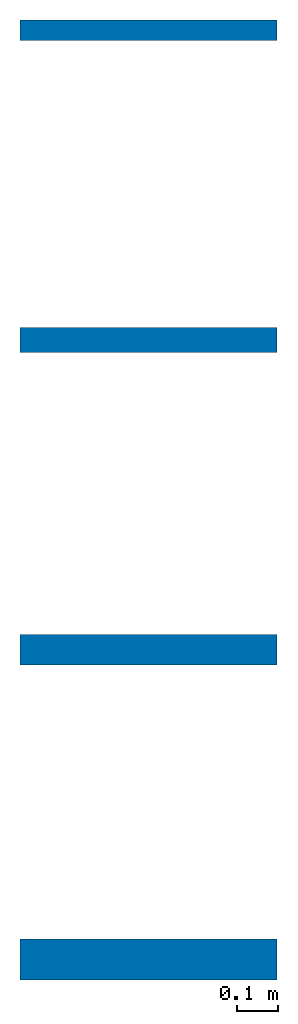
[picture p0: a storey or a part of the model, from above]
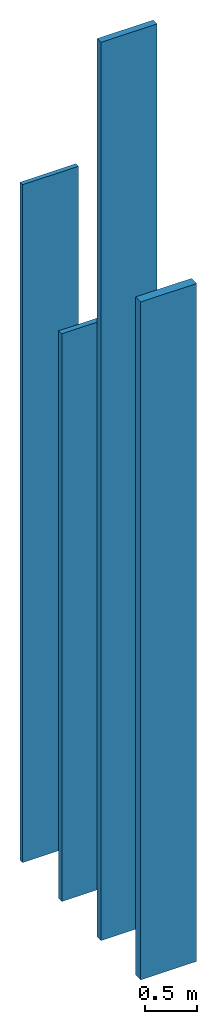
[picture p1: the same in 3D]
Properties of the parts of a building model (IFC2X3)

# File
Description: ViewDefinition [CoordinationView_V2.0]
File name: 0001
Time: 2018-02-28T12:43:13
Written by: The EXPRESS Data Manager Version 5.02.0100.07 : 28 Aug 2013
Made in: 20140606_1530(x64) - Exporter 15.6.0.0 - Alternate UI 15.6.0.0
Comment: STEP Physical File produced by: The EXPRESS Data Manager Version 5.02.0100.07 : 28 Aug 2013 * Module: EDMstepFileFactory/EDMstandAlone * Creation date: Wed Feb 28 12:43:13 2018 * Host: BRUTUS-02 * Database: C:\Users\MIGUEL~1\AppData\Local\Temp\{2AA0D388-3C4A-43AB-BBA2-5D648CE83F9A}\ifc * Database version: 5507 * Database creation date: Wed Feb 28 12:43:13 2018 * Schema: IFC2X3 * Model: DataRepository.ifc * Model creation date: Wed Feb 28 12:43:13 2018 * Header model: DataRepository.ifc_HeaderModel * Header model creation date: Wed Feb 28 12:43:13 2018 * EDMuser: sdai-user * EDMgroup: sdai-group * License ID and type: 5605 : Permanent license. Expiry date: * EDMstepFileFactory options: 020000

# IfcProject, 0001
LongName: Project Name; Phase: Project Status

# IfcSite, Default
RefLatitude: 42, 21, 30, 344238; RefLongitude: -71, -3, -35, -194702; RefElevation: 0 mm
Other - Category: Project Information; Client Name: Owner; Project Address: ## Street City, State Zip; Project Issue Date: Issue Date; Project Name: Project Name; Project Number: 0001; Project Status: Project Status

# IfcBuilding
Pset_BuildingCommon - NumberOfStoreys: 1
Other - Category: Project Information; Client Name: Owner; Project Address: ## Street City, State Zip; Project Issue Date: Issue Date; Project Name: Project Name; Project Number: 0001; Project Status: Project Status

# IfcBuildingStorey, Референтни ниво
LongName: Референтни ниво; Elevation: 0 mm
Other - Category: Levels; Family Name: Level; Family: Level: 8mm Head; Family and Type: Level: 8mm Head; Type: Level: 8mm Head; Type Id: Level: 8mm Head
Constraints - Elevation: 0 mm; Elevation Base: Project Base Point
Dimensions - Computation Height: 0 mm
Identity Data - Structural: no; Building Story: yes; Name: Референтни ниво; Type Name: 8mm Head
Graphics - Color: 0; Line Pattern: Center; Line Weight: 1; Symbol at End 1 Default: no; Symbol at End 2 Default: yes

# IfcWallStandardCase: Basic Wall:Knauf Insulation - Decibel - 100 mm - 100 x 8000 x 625 mm, Basic Wall:Knauf Insulation - Decibel - 100 mm - 100 x 8000 x 625 mm:207778
In: Референтни ниво
Type - PredefinedType: STANDARD; Material: Knauf Insulation - Decibel - 100 mm - 100 x 8000 x 625 mm 100 mm
Type - Analytical Properties - Roughness: 3; Absorptance: 0.7; Heat Transfer Coefficient (U): 0.38; Thermal mass: 958.5; Thermal Resistance (R): 2.63158
Type - Construction - Function: Exterior; Wrapping at Inserts: Do not wrap; Width: 100 mm
Type - Graphics - Coarse Scale Fill Color: 3951475
Type - Identity Data - Description: proizvod od staklene mineralne vune sa ECOSE® Technology. Pruža visoku zaštitu u pogledu termičke, zvučne i zaštite od požara. Proizvodi se sa širinom od 625mm.; KontaktE-mail: edin.dalifi@knaufinsulation.com; KontaktTelefon: +3811113310800; Manufacturer: Knauf Insulation; Model: Decibel; No.: 85; Type Comments: namenjen je za primenu u unutrašnjim zidovima kao ispuna koja apsorbuje zvuk u pregradnim zidovima sa visokim akustičkim zahtevima kada su u pitanju suvomontažne konstrukcije sa gips-kartonskim pločama. Ukoliko se materijal upotrebljava u konstrukcijama sa različitim režimima grejanja, treba postaviti parnu branu sa toplije strane izolacionog materijala, ka strani koja je okrenuta grejanom prostoru, da bi se sprečilo prodiranje unutrašnje vlage u materijal.; Type Name: Knauf Insulation - Decibel - 100 mm - 100 x 8000 x 625 mm; URL: http://www.knaufinsulation.rs/sr/staklena-vuna/decibel
Type - Materials and Finishes - Structural Material: Knauf Insulation - Decibel - 100 mm - 100 x 8000 x 625 mm
Type - Other - Category: Walls; Family Name: Basic Wall
Constraints - Base Constraint: Level: Референтни ниво; Base Extension Distance: 0 mm; Base is Attached: no; Base Offset: 0 mm; Location Line: Wall Centerline; Related to Mass: no; Room Bounding: yes; Top Extension Distance: 0 mm; Top is Attached: no; Top Offset: 0 mm; Unconnected Height: 8000 mm
Dimensions - Area: 5 m2; Length: 625 mm; Volume: 0.5 m3
Other - Family: Basic Wall: Knauf Insulation - Decibel - 100 mm - 100 x 8000 x 625 mm; Family and Type: Basic Wall: Knauf Insulation - Decibel - 100 mm - 100 x 8000 x 625 mm; Type: Basic Wall: Knauf Insulation - Decibel - 100 mm - 100 x 8000 x 625 mm; Type Id: Basic Wall: Knauf Insulation - Decibel - 100 mm - 100 x 8000 x 625 mm
Phasing - Phase Created: New Construction
Structural - Enable Analytical Model: no; Structural: no; Structural Usage: Non-bearing
Pset_WallCommon - LoadBearing: no; ExtendToStructure: no; IsExternal: yes; Reference: Knauf Insulation - Decibel - 100 mm - 100 x 8000 x 625 mm; ThermalTransmittance: 0.38 kg/K/s3
Pset_ManufacturerTypeInformation - Manufacturer: Knauf Insulation
Knauf Insulation Materijali - Zidovi - No.: 85

# IfcWallStandardCase: Basic Wall:Knauf Insulation - Decibel - 50 mm -50 x 8000 x 625 mm, Basic Wall:Knauf Insulation - Decibel - 50 mm -50 x 8000 x 625 mm:207353
In: Референтни ниво
Type - PredefinedType: STANDARD; Material: Knauf Insulation - Decibel - 50 mm - 50 x 8000 x 625 mm 50 mm
Type - Analytical Properties - Absorptance: 0.7; Heat Transfer Coefficient (U): 0.76; Roughness: 3; Thermal mass: 479.25; Thermal Resistance (R): 1.31579
Type - Construction - Function: Exterior; Width: 50 mm; Wrapping at Inserts: Do not wrap
Type - Graphics - Coarse Scale Fill Color: 3951475
Type - Identity Data - Description: proizvod od staklene mineralne vune sa ECOSE® Technology. Pruža visoku zaštitu u pogledu termičke, zvučne i zaštite od požara. Proizvodi se sa širinom od 625mm.; KontaktE-mail: edin.dalifi@knaufinsulation.com; KontaktTelefon: +3811113310800; Manufacturer: Knauf Insulation; Model: Decibel; No.: 82; Type Comments: namenjen je za primenu u unutrašnjim zidovima kao ispuna koja apsorbuje zvuk u pregradnim zidovima sa visokim akustičkim zahtevima kada su u pitanju suvomontažne konstrukcije sa gips-kartonskim pločama. Ukoliko se materijal upotrebljava u konstrukcijama sa različitim režimima grejanja, treba postaviti parnu branu sa toplije strane izolacionog materijala, ka strani koja je okrenuta grejanom prostoru, da bi se sprečilo prodiranje unutrašnje vlage u materijal.; Type Name: Knauf Insulation - Decibel - 50 mm -50 x 8000 x 625 mm; URL: http://www.knaufinsulation.rs/sr/staklena-vuna/decibel
Type - Materials and Finishes - Structural Material: Knauf Insulation - Decibel - 50 mm - 50 x 8000 x 625 mm
Type - Other - Category: Walls; Family Name: Basic Wall
Constraints - Base Constraint: Level: Референтни ниво; Base Extension Distance: 0 mm; Base is Attached: no; Base Offset: 0 mm; Location Line: Wall Centerline; Related to Mass: no; Room Bounding: yes; Top Extension Distance: 0 mm; Top is Attached: no; Top Offset: 0 mm; Unconnected Height: 8000 mm
Dimensions - Area: 5 m2; Length: 625 mm; Volume: 0.25 m3
Other - Family: Basic Wall: Knauf Insulation - Decibel - 50 mm -50 x 8000 x 625 mm; Family and Type: Basic Wall: Knauf Insulation - Decibel - 50 mm -50 x 8000 x 625 mm; Type: Basic Wall: Knauf Insulation - Decibel - 50 mm -50 x 8000 x 625 mm; Type Id: Basic Wall: Knauf Insulation - Decibel - 50 mm -50 x 8000 x 625 mm
Phasing - Phase Created: New Construction
Structural - Enable Analytical Model: no; Structural: no; Structural Usage: Non-bearing
Pset_WallCommon - Reference: Knauf Insulation - Decibel - 50 mm -50 x 8000 x 625 mm; LoadBearing: no; ExtendToStructure: no; IsExternal: yes; ThermalTransmittance: 0.76 kg/K/s3
Pset_ManufacturerTypeInformation - Manufacturer: Knauf Insulation
Knauf Insulation Materijali - Zidovi - No.: 82

# IfcWallStandardCase: Basic Wall:Knauf Insulation - Decibel - 60 mm - 60 x 6700 x 625 mm, Basic Wall:Knauf Insulation - Decibel - 60 mm - 60 x 6700 x 625 mm:207522
In: Референтни ниво
Type - PredefinedType: STANDARD; Material: Knauf Insulation - Decibel - 60 mm - 60 x 6700 x 625 mm 60 mm
Type - Analytical Properties - Roughness: 3; Absorptance: 0.7; Heat Transfer Coefficient (U): 0.633333; Thermal mass: 575.1; Thermal Resistance (R): 1.57895
Type - Construction - Function: Exterior; Wrapping at Inserts: Do not wrap; Width: 60 mm
Type - Graphics - Coarse Scale Fill Color: 3951475
Type - Identity Data - Description: proizvod od staklene mineralne vune sa ECOSE® Technology. Pruža visoku zaštitu u pogledu termičke, zvučne i zaštite od požara. Proizvodi se sa širinom od 625mm.; KontaktE-mail: edin.dalifi@knaufinsulation.com; KontaktTelefon: +3811113310800; Manufacturer: Knauf Insulation; Model: Decibel; No.: 83; Type Comments: namenjen je za primenu u unutrašnjim zidovima kao ispuna koja apsorbuje zvuk u pregradnim zidovima sa visokim akustičkim zahtevima kada su u pitanju suvomontažne konstrukcije sa gips-kartonskim pločama. Ukoliko se materijal upotrebljava u konstrukcijama sa različitim režimima grejanja, treba postaviti parnu branu sa toplije strane izolacionog materijala, ka strani koja je okrenuta grejanom prostoru, da bi se sprečilo prodiranje unutrašnje vlage u materijal.; Type Name: Knauf Insulation - Decibel - 60 mm - 60 x 6700 x 625 mm; URL: http://www.knaufinsulation.rs/sr/staklena-vuna/decibel
Type - Materials and Finishes - Structural Material: Knauf Insulation - Decibel - 60 mm - 60 x 6700 x 625 mm
Type - Other - Category: Walls; Family Name: Basic Wall
Constraints - Base Constraint: Level: Референтни ниво; Base Extension Distance: 0 mm; Base is Attached: no; Base Offset: 0 mm; Location Line: Wall Centerline; Related to Mass: no; Room Bounding: yes; Top Extension Distance: 0 mm; Top is Attached: no; Top Offset: 0 mm; Unconnected Height: 6700 mm
Dimensions - Area: 4.1875 m2; Length: 625 mm; Volume: 0.25125 m3
Other - Family: Basic Wall: Knauf Insulation - Decibel - 60 mm - 60 x 6700 x 625 mm; Family and Type: Basic Wall: Knauf Insulation - Decibel - 60 mm - 60 x 6700 x 625 mm; Type: Basic Wall: Knauf Insulation - Decibel - 60 mm - 60 x 6700 x 625 mm; Type Id: Basic Wall: Knauf Insulation - Decibel - 60 mm - 60 x 6700 x 625 mm
Phasing - Phase Created: New Construction
Structural - Enable Analytical Model: no; Structural: no; Structural Usage: Non-bearing
Pset_WallCommon - LoadBearing: no; ExtendToStructure: no; IsExternal: yes; Reference: Knauf Insulation - Decibel - 60 mm - 60 x 6700 x 625 mm; ThermalTransmittance: 0.633333 kg/K/s3
Pset_ManufacturerTypeInformation - Manufacturer: Knauf Insulation
Knauf Insulation Materijali - Zidovi - No.: 83

# IfcWallStandardCase: Basic Wall:Knauf Insulation - Decibel - 75 mm - 75 x 10600 x 625 mm, Basic Wall:Knauf Insulation - Decibel - 75 mm - 75 x 10600 x 625 mm:207662
In: Референтни ниво
Type - PredefinedType: STANDARD; Material: Knauf Insulation - Decibel - 75 mm - 75 x 10600 x 625 mm 75 mm
Type - Analytical Properties - Roughness: 3; Absorptance: 0.7; Heat Transfer Coefficient (U): 0.506667; Thermal mass: 718.875; Thermal Resistance (R): 1.97368
Type - Construction - Function: Exterior; Wrapping at Inserts: Do not wrap; Width: 75 mm
Type - Graphics - Coarse Scale Fill Color: 3951475
Type - Identity Data - Description: proizvod od staklene mineralne vune sa ECOSE® Technology. Pruža visoku zaštitu u pogledu termičke, zvučne i zaštite od požara. Proizvodi se sa širinom od 625mm.; KontaktE-mail: edin.dalifi@knaufinsulation.com; KontaktTelefon: +3811113310800; Manufacturer: Knauf Insulation; Model: Decibel; No.: 84; Type Comments: namenjen je za primenu u unutrašnjim zidovima kao ispuna koja apsorbuje zvuk u pregradnim zidovima sa visokim akustičkim zahtevima kada su u pitanju suvomontažne konstrukcije sa gips-kartonskim pločama. Ukoliko se materijal upotrebljava u konstrukcijama sa različitim režimima grejanja, treba postaviti parnu branu sa toplije strane izolacionog materijala, ka strani koja je okrenuta grejanom prostoru, da bi se sprečilo prodiranje unutrašnje vlage u materijal.; Type Name: Knauf Insulation - Decibel - 75 mm - 75 x 10600 x 625 mm; URL: http://www.knaufinsulation.rs/sr/staklena-vuna/decibel
Type - Materials and Finishes - Structural Material: Knauf Insulation - Decibel - 75 mm - 75 x 10600 x 625 mm
Type - Other - Category: Walls; Family Name: Basic Wall
Constraints - Base Constraint: Level: Референтни ниво; Base Extension Distance: 0 mm; Base is Attached: no; Base Offset: 0 mm; Location Line: Wall Centerline; Related to Mass: no; Room Bounding: yes; Top Extension Distance: 0 mm; Top is Attached: no; Top Offset: 0 mm; Unconnected Height: 10600 mm
Dimensions - Area: 6.625 m2; Length: 625 mm; Volume: 0.496875 m3
Other - Family: Basic Wall: Knauf Insulation - Decibel - 75 mm - 75 x 10600 x 625 mm; Family and Type: Basic Wall: Knauf Insulation - Decibel - 75 mm - 75 x 10600 x 625 mm; Type: Basic Wall: Knauf Insulation - Decibel - 75 mm - 75 x 10600 x 625 mm; Type Id: Basic Wall: Knauf Insulation - Decibel - 75 mm - 75 x 10600 x 625 mm
Phasing - Phase Created: New Construction
Structural - Enable Analytical Model: no; Structural: no; Structural Usage: Non-bearing
Pset_WallCommon - LoadBearing: no; ExtendToStructure: no; IsExternal: yes; Reference: Knauf Insulation - Decibel - 75 mm - 75 x 10600 x 625 mm; ThermalTransmittance: 0.506667 kg/K/s3
Pset_ManufacturerTypeInformation - Manufacturer: Knauf Insulation
Knauf Insulation Materijali - Zidovi - No.: 84
